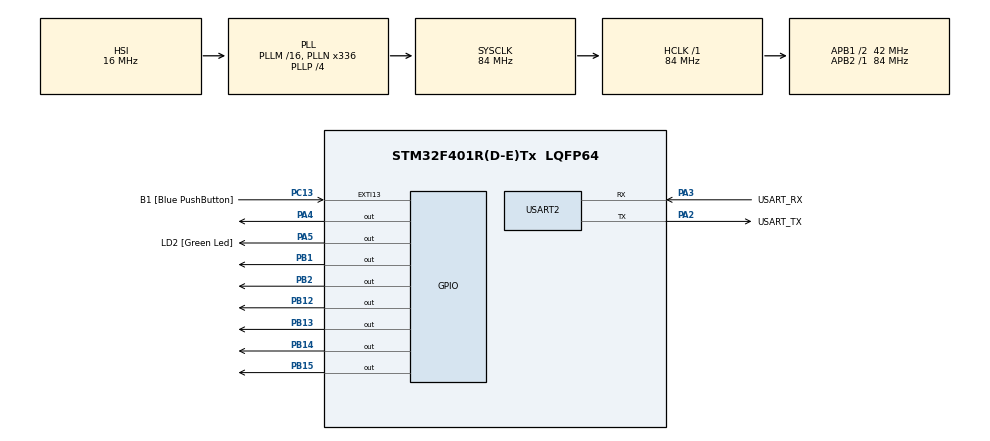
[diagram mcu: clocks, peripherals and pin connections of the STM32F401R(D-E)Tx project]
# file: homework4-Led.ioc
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Mcu.Family=STM32F4
Mcu.Name=STM32F401R(D-E)Tx
Mcu.Package=LQFP64
NVIC.PriorityGroup=NVIC_PRIORITYGROUP_0
PA13.GPIO_Label=TMS
PA13.Mode=Serial_Wire
PA13.Signal=SYS_JTMS-SWDIO
PA14.GPIO_Label=TCK
PA14.Mode=Serial_Wire
PA14.Signal=SYS_JTCK-SWCLK
PA2.GPIO_Label=USART_TX
PA2.GPIO_Mode=GPIO_MODE_AF_PP
PA2.GPIO_PuPd=GPIO_NOPULL
PA2.GPIO_Speed=GPIO_SPEED_FREQ_LOW
PA2.Mode=Asynchronous
PA2.Signal=USART2_TX
PA3.GPIO_Label=USART_RX
PA3.GPIO_Mode=GPIO_MODE_AF_PP
PA3.GPIO_PuPd=GPIO_NOPULL
PA3.GPIO_Speed=GPIO_SPEED_FREQ_LOW
PA3.Mode=Asynchronous
PA3.Signal=USART2_RX
PA4.Signal=GPIO_Output
PA5.GPIO_Label=LD2 [Green Led]
PA5.GPIO_Mode=GPIO_MODE_OUTPUT_PP
PA5.GPIO_PuPd=GPIO_NOPULL
PA5.GPIO_Speed=GPIO_SPEED_FREQ_LOW
PA5.Signal=GPIO_Output
PB1.Signal=GPIO_Output
PB12.Signal=GPIO_Output
PB13.Signal=GPIO_Output
PB14.Signal=GPIO_Output
PB15.Signal=GPIO_Output
PB2.Signal=GPIO_Output
PB3.GPIO_Label=SWO
PB3.Signal=SYS_JTDO-SWO
PC13-ANTI_TAMP.GPIO_Label=B1 [Blue PushButton]
PC13-ANTI_TAMP.GPIO_ModeDefaultEXTI=GPIO_MODE_IT_FALLING
PC13-ANTI_TAMP.GPIO_PuPd=GPIO_NOPULL
PC13-ANTI_TAMP.Signal=GPXTI13
PC14-OSC32_IN.Mode=LSE-External-Oscillator
PC14-OSC32_IN.Signal=RCC_OSC32_IN
PC15-OSC32_OUT.Mode=LSE-External-Oscillator
PC15-OSC32_OUT.Signal=RCC_OSC32_OUT
PH0\ -\ OSC_IN.Mode=HSE-External-Clock-Source
PH0\ -\ OSC_IN.Signal=RCC_OSC_IN
PH1\ -\ OSC_OUT.Mode=HSE-External-Clock-Source
PH1\ -\ OSC_OUT.Signal=RCC_OSC_OUT
ProjectManager.HeapSize=0x200
ProjectManager.StackSize=0x400
ProjectManager.TargetToolchain=STM32CubeIDE
RCC.48MHZClocksFreq_Value=48000000
RCC.AHBFreq_Value=84000000
RCC.APB1CLKDivider=RCC_HCLK_DIV2
RCC.APB1Freq_Value=42000000
RCC.APB1TimFreq_Value=84000000
RCC.APB2Freq_Value=84000000
RCC.APB2TimFreq_Value=84000000
RCC.CortexFreq_Value=84000000
RCC.HCLKFreq_Value=84000000
RCC.HSE_VALUE=8000000
RCC.HSI_VALUE=16000000
RCC.PLLN=336
RCC.PLLP=RCC_PLLP_DIV4
RCC.PLLQ=7
RCC.SYSCLKFreq_VALUE=84000000
RCC.SYSCLKSource=RCC_SYSCLKSOURCE_PLLCLK
RCC.VCOOutputFreq_Value=336000000
USART2.VirtualMode=VM_ASYNC
board=NUCLEO-F401RE

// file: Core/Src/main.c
/* USER CODE BEGIN Header */
/**
  ******************************************************************************
  * @file           : main.c
  * @brief          : Main program body
  ******************************************************************************
  * @attention
  *
  * Copyright (c) 2024 STMicroelectronics.
  * All rights reserved.
  *
  * This software is licensed under terms that can be found in the LICENSE file
  * in the root directory of this software component.
  * If no LICENSE file comes with this software, it is provided AS-IS.
  *
  ******************************************************************************
  */
/* USER CODE END Header */
#include "main.h"

/* USER CODE BEGIN Includes */
#include "PMDB16_LCD.h"
#include <string.h>
/* USER CODE END Includes */

UART_HandleTypeDef huart2;
DMA_HandleTypeDef hdma_usart2_tx;

void SystemClock_Config(void);
static void MX_GPIO_Init(void);
static void MX_DMA_Init(void);
static void MX_USART2_UART_Init(void);

/* USER CODE BEGIN 0 */

int members_index;

 char *members[] = {"Riccardo","Alessio", "Sofia", "Anna", "Emma"};

 int length = sizeof(members)/sizeof(char*);

 void insertion_sort(char* arr[], int n)
 {
     for (int i = 1; i < n; ++i) {
         char* key = arr[i];
         int j = i - 1;

         /* Move elements of arr[0..i-1], that are
            greater than key, to one position ahead
            of their current position */
         while (j >= 0 && strcmp(arr[j], key)>0) {
             arr[j + 1] = arr[j];
             j = j - 1;
         }
         arr[j + 1] = key;
     }
 }

/* USER CODE END 0 */

int main(void)
{

  /* USER CODE BEGIN 1 */
	insertion_sort(members, length);
  /* USER CODE END 1 */

  /* MCU Configuration--------------------------------------------------------*/

  /* Reset of all peripherals, Initializes the Flash interface and the Systick. */
  HAL_Init();

  /* Configure the system clock */
  SystemClock_Config();

  /* Initialize all configured peripherals */
  MX_GPIO_Init();
  MX_DMA_Init();
  MX_USART2_UART_Init();
  /* USER CODE BEGIN 2 */

  lcd_initialize();
  lcd_backlight_ON();

  /* USER CODE END 2 */

  /* Infinite loop */
  /* USER CODE BEGIN WHILE */

  int counter = 1;
  lcd_println(members[0], 1);
  HAL_Delay(1000);
  while (1)
  {

	  lcd_clear();
	  lcd_println(members[(counter + 1) % length], 1);
	  lcd_println(members[(counter ) % length], 0);
	  counter = (counter + 1)%length;
	  HAL_Delay(1000);

    /* USER CODE END WHILE */

  }
}

void SystemClock_Config(void)
{
  RCC_OscInitTypeDef RCC_OscInitStruct = {0};
  RCC_ClkInitTypeDef RCC_ClkInitStruct = {0};

  /** Configure the main internal regulator output voltage
  */
  __HAL_RCC_PWR_CLK_ENABLE();
  __HAL_PWR_VOLTAGESCALING_CONFIG(PWR_REGULATOR_VOLTAGE_SCALE2);

  /** Initializes the RCC Oscillators according to the specified parameters
  * in the RCC_OscInitTypeDef structure.
  */
  RCC_OscInitStruct.OscillatorType = RCC_OSCILLATORTYPE_HSI;
  RCC_OscInitStruct.HSIState = RCC_HSI_ON;
  RCC_OscInitStruct.HSICalibrationValue = RCC_HSICALIBRATION_DEFAULT;
  RCC_OscInitStruct.PLL.PLLState = RCC_PLL_ON;
  RCC_OscInitStruct.PLL.PLLSource = RCC_PLLSOURCE_HSI;
  RCC_OscInitStruct.PLL.PLLM = 16;
  RCC_OscInitStruct.PLL.PLLN = 336;
  RCC_OscInitStruct.PLL.PLLP = RCC_PLLP_DIV4;
  RCC_OscInitStruct.PLL.PLLQ = 7;
  if (HAL_RCC_OscConfig(&RCC_OscInitStruct) != HAL_OK)
  {
    Error_Handler();
  }

  /** Initializes the CPU, AHB and APB buses clocks
  */
  RCC_ClkInitStruct.ClockType = RCC_CLOCKTYPE_HCLK|RCC_CLOCKTYPE_SYSCLK
                              |RCC_CLOCKTYPE_PCLK1|RCC_CLOCKTYPE_PCLK2;
  RCC_ClkInitStruct.SYSCLKSource = RCC_SYSCLKSOURCE_PLLCLK;
  RCC_ClkInitStruct.AHBCLKDivider = RCC_SYSCLK_DIV1;
  RCC_ClkInitStruct.APB1CLKDivider = RCC_HCLK_DIV2;
  RCC_ClkInitStruct.APB2CLKDivider = RCC_HCLK_DIV1;

  if (HAL_RCC_ClockConfig(&RCC_ClkInitStruct, FLASH_LATENCY_2) != HAL_OK)
  {
    Error_Handler();
  }
}

static void MX_USART2_UART_Init(void)
{

  huart2.Instance = USART2;
  huart2.Init.BaudRate = 115200;
  huart2.Init.WordLength = UART_WORDLENGTH_8B;
  huart2.Init.StopBits = UART_STOPBITS_1;
  huart2.Init.Parity = UART_PARITY_NONE;
  huart2.Init.Mode = UART_MODE_TX_RX;
  huart2.Init.HwFlowCtl = UART_HWCONTROL_NONE;
  huart2.Init.OverSampling = UART_OVERSAMPLING_16;
  if (HAL_UART_Init(&huart2) != HAL_OK)
  {
    Error_Handler();
  }

}

static void MX_DMA_Init(void)
{

  /* DMA controller clock enable */
  __HAL_RCC_DMA1_CLK_ENABLE();

  /* DMA interrupt init */
  /* DMA1_Stream6_IRQn interrupt configuration */
  HAL_NVIC_SetPriority(DMA1_Stream6_IRQn, 0, 0);
  HAL_NVIC_EnableIRQ(DMA1_Stream6_IRQn);

}

static void MX_GPIO_Init(void)
{
  GPIO_InitTypeDef GPIO_InitStruct = {0};

  /* GPIO Ports Clock Enable */
  __HAL_RCC_GPIOC_CLK_ENABLE();
  __HAL_RCC_GPIOH_CLK_ENABLE();
  __HAL_RCC_GPIOA_CLK_ENABLE();
  __HAL_RCC_GPIOB_CLK_ENABLE();

  /*Configure GPIO pin Output Level */
  HAL_GPIO_WritePin(GPIOA, LCD_BL_ON_Pin|GPIO_PIN_5, GPIO_PIN_RESET);

  /*Configure GPIO pin Output Level */
  HAL_GPIO_WritePin(GPIOB, LCD_E_Pin|LCD_RS_Pin|LCD_D4_Pin|LCD_D5_Pin
                          |LCD_D6_Pin|LCD_D7_Pin, GPIO_PIN_RESET);

  /*Configure GPIO pin : B1_Pin */
  GPIO_InitStruct.Pin = B1_Pin;
  GPIO_InitStruct.Mode = GPIO_MODE_IT_FALLING;
  GPIO_InitStruct.Pull = GPIO_NOPULL;
  HAL_GPIO_Init(B1_GPIO_Port, &GPIO_InitStruct);

  /*Configure GPIO pins : LCD_BL_ON_Pin PA5 */
  GPIO_InitStruct.Pin = LCD_BL_ON_Pin|GPIO_PIN_5;
  GPIO_InitStruct.Mode = GPIO_MODE_OUTPUT_PP;
  GPIO_InitStruct.Pull = GPIO_NOPULL;
  GPIO_InitStruct.Speed = GPIO_SPEED_FREQ_LOW;
  HAL_GPIO_Init(GPIOA, &GPIO_InitStruct);

  /*Configure GPIO pins : LCD_E_Pin LCD_RS_Pin LCD_D4_Pin LCD_D5_Pin
                           LCD_D6_Pin LCD_D7_Pin */
  GPIO_InitStruct.Pin = LCD_E_Pin|LCD_RS_Pin|LCD_D4_Pin|LCD_D5_Pin
                          |LCD_D6_Pin|LCD_D7_Pin;
  GPIO_InitStruct.Mode = GPIO_MODE_OUTPUT_PP;
  GPIO_InitStruct.Pull = GPIO_NOPULL;
  GPIO_InitStruct.Speed = GPIO_SPEED_FREQ_LOW;
  HAL_GPIO_Init(GPIOB, &GPIO_InitStruct);

}

void Error_Handler(void)
{
  __disable_irq();
  while (1)
  {
  }
}
